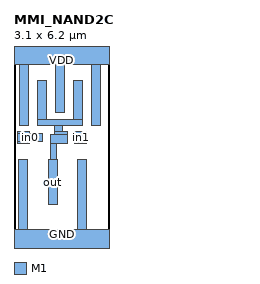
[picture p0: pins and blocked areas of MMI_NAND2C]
MACRO MMI_NAND2C
	CLASS CORE ;
	FOREIGN MMI_NAND2C 0 0 ;
	SIZE 3.1 BY 6.2 ;
	SYMMETRY X Y ;
	SITE CORE1 ;
	PIN out
		DIRECTION output ;
		USE SIGNAL ;
		PORT
			LAYER M1 ;
			RECT 0.775 3.995 1.055 5.27 ;
			LAYER M1 ;
			RECT 1.955 3.995 2.235 5.27 ;
			LAYER M1 ;
			RECT 0.755 3.8 2.245 3.995 ;
			LAYER M1 ;
			RECT 1.31 3.6 1.595 3.8 ;
			LAYER M1 ;
			RECT 1.31 3.505 1.74 3.6 ;
			LAYER M1 ;
			RECT 1.205 3.22 1.74 3.505 ;
			LAYER M1 ;
			RECT 1.205 2.69 1.4 3.22 ;
			LAYER M1 ;
			RECT 1.125 1.22 1.405 2.69 ;
		END
		AntennaDiffArea 2.0328 ;
	END out
	PIN in1
		DIRECTION input ;
		USE SIGNAL ;
		PORT
			LAYER M1 ;
			RECT 1.98 3.22 2.36 3.6 ;
		END
		AntennaGateArea 0.924 ;
	END in1
	PIN GND
		DIRECTION inout ;
		USE GROUND ;
		PORT
			LAYER M1 ;
			RECT 0.16 0.42 0.44 2.69 ;
			LAYER M1 ;
			RECT 2.085 0.42 2.365 2.69 ;
			LAYER M1 ;
			RECT 0 -0.42 3.1 0.42 ;
		END
	END GND
	PIN VDD
		DIRECTION inout ;
		USE POWER ;
		PORT
			LAYER M1 ;
			RECT 0 5.78 3.1 6.62 ;
			LAYER M1 ;
			RECT 0.185 3.8 0.465 5.78 ;
			LAYER M1 ;
			RECT 1.365 4.21 1.645 5.78 ;
			LAYER M1 ;
			RECT 2.545 3.8 2.825 5.78 ;
		END
	END VDD
	PIN in0
		DIRECTION input ;
		USE SIGNAL ;
		PORT
			LAYER M1 ;
			RECT 0.12 3.555 0.5 3.6 ;
			LAYER M1 ;
			RECT 0.12 3.55 0.655 3.555 ;
			LAYER M1 ;
			RECT 0.12 3.27 0.935 3.55 ;
			LAYER M1 ;
			RECT 0.12 3.22 0.5 3.27 ;
		END
		AntennaGateArea 0.924 ;
	END in0
	OBS
	END
END MMI_NAND2C
